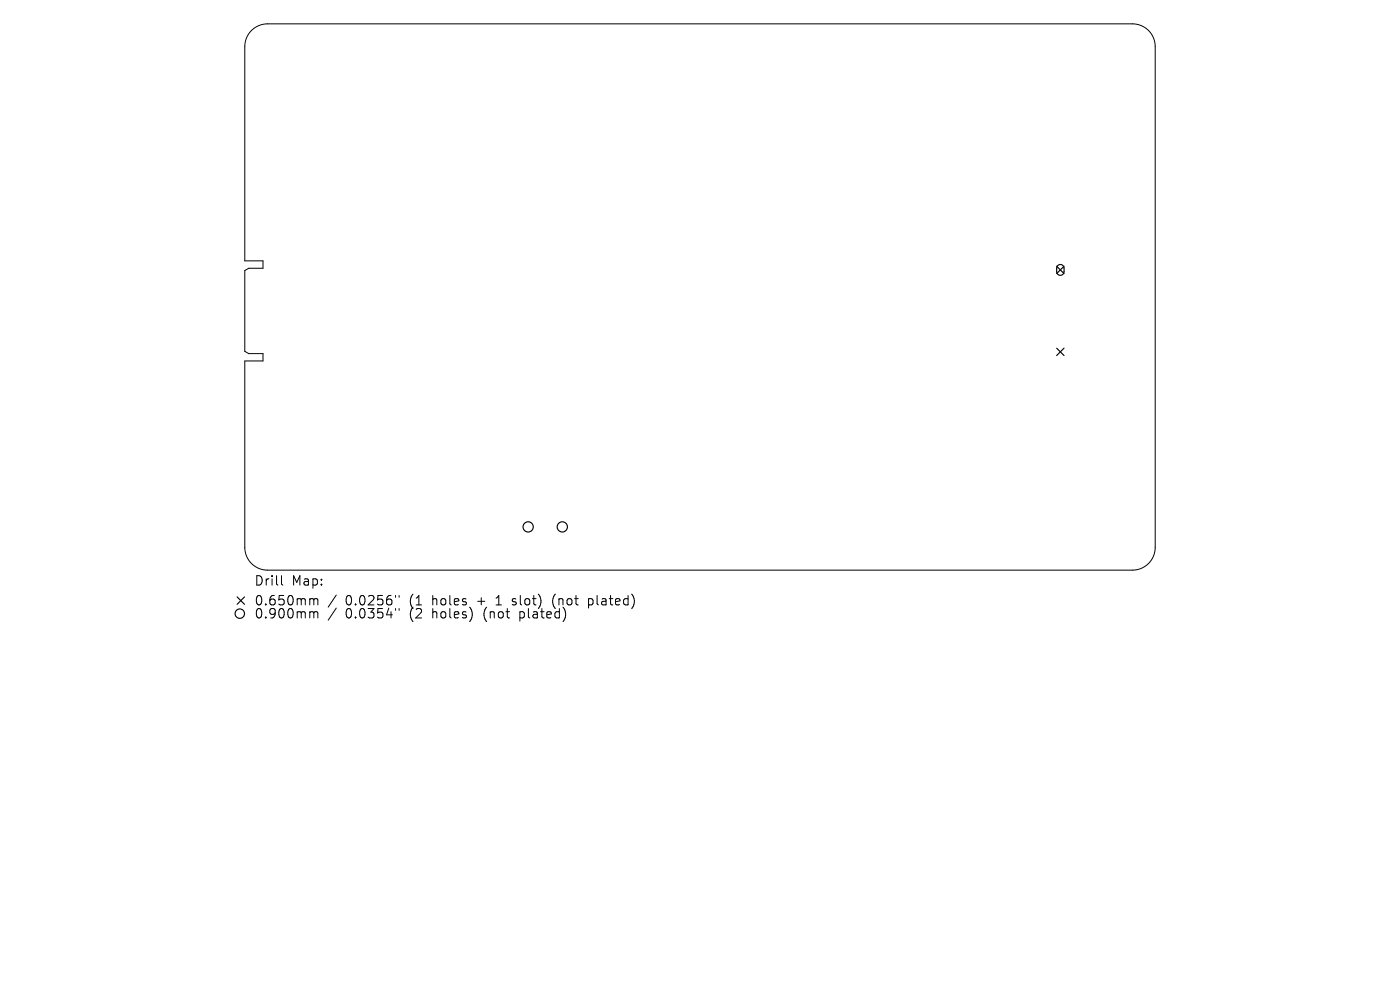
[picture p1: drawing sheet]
<svg xmlns="http://www.w3.org/2000/svg" width="297mm" height="210mm" viewBox="0 0 297 210" stroke-linecap="round" stroke-linejoin="round" font-family="sans-serif">
<defs><g id="words">
<g font-size="2.8">
<text x="53.9" y="124.5">Drill</text>
<text x="61.9" y="124.5">Map:</text>
<text x="53.9" y="128.7">0.650mm</text>
<text x="53.9" y="131.5">0.900mm</text>
<text x="73.3" y="128.7">0.0256&quot;</text>
<text x="73.3" y="131.5">0.0354&quot;</text>
<text x="87" y="128.7">(1</text>
<text x="87" y="131.5">(2</text>
<text x="92" y="128.7">holes</text>
<text x="92" y="131.5">holes)</text>
<text x="101.7" y="128.7">+</text>
<text x="103.1" y="131.5">(not</text>
<text x="105.9" y="128.7">1</text>
<text x="109.6" y="128.7">slot)</text>
<text x="110.9" y="131.5">plated)</text>
<text x="118.2" y="128.7">(not</text>
<text x="126.1" y="128.7">plated)</text>
</g>
</g></defs>
<g fill="none" stroke="#000" stroke-width=".21">
<path d="M53.3 6.5a4.8 4.8 0 0 1 3.5-1.4h183.4a4.8 4.8 0 0 1 4.9 4.8v106.2a4.8 4.8 0 0 1-4.9 4.8h-183.4a4.8 4.8 0 0 1-4.9-4.8v-39.5h3.9v-1.6h-3l-.9-.5v-17.1l.9-.5h3v-1.6h-3.9v-45.4a4.8 4.8 0 0 1 1.4-3.4zM59.7 122.1v1.7l.3 .3M66 127l.5 .1 .1 .2M66 129.8l.5 .1 .1 .1M66.6 127.3l.3-.3 .4 .1 .1 1.2M66.6 127.3v1M66.6 130v1.1M66.6 130l.3-.2 .4 .1 .1 1.2M71.3 126.2l-1.7 2.6M71.3 129l-1.7 2.6M83.9 126.3v.4M83.9 129.1v.4"/>
<path d="M84.7 126.3v.4M84.7 129.1v.4M108.7 128.2l.2 .1M108.8 127.1v.5M117.5 126.4l-.3 1 .2 1.1M124.9 127v2M124.9 128.2l.5 .1M125.4 127l-.5 .1"/>
</g>
<g fill="none" stroke="#000" stroke-width=".24">
<path d="M224.2 56.5l1.5 1.5M224.4 56.3a.78 .78 0 0 1 .8-.1 .78 .78 0 0 1 .5 .7v.7a.78 .78 0 0 1-.8 .8 .78 .78 0 0 1-.7-.8v-.8zM225.7 56.5l-1.5 1.5M224.2 73.9l1.5 1.5M225.7 73.9l-1.5 1.5M50.3 126.6l1.6 1.6M51.9 126.6l-1.6 1.6"/>
<circle cx="112" cy="111.8" r="1.09"/>
<circle cx="119.3" cy="111.8" r="1.09"/>
<circle cx="50.9" cy="130.2" r="1"/>
</g>
<use href="#words"/>
</svg>
